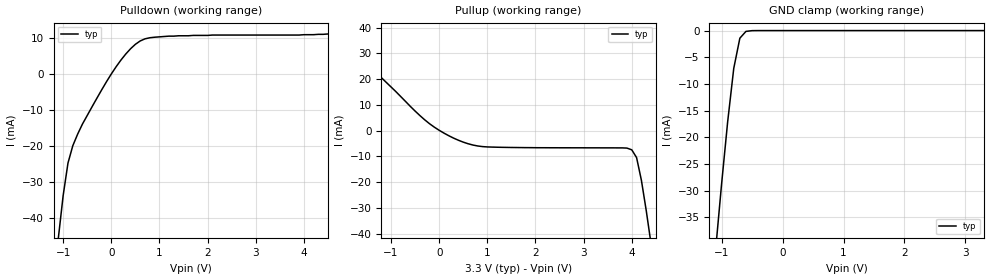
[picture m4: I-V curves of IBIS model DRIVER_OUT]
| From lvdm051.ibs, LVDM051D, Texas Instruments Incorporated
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|   Driver Output  MODEL
[Model]   DRIVER_OUT
Model_type   3-state
| Signals   1Y,1Z,2Y,2Z
Vmeas = 1.2V   |Reference voltage for timing measurements
Cref = 5pF   |Timing specification test load capacitance value
Rref = 50   |Note: 50 Ohm load; single ended configuration
Vref = 1.18V   |Timing specification test load voltage
| variable   typ   min   max
C_comp   1.0pF   NA   NA
|   typ   min   max
[Temperature Range]   25.0   NA   NA
[Voltage range]   3.3V   3.0V   3.6V
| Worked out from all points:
|   slope of the pulldown table from 0 to 0.495 V, typ, clamps not added: 60.6 ohm
|   slope of the pullup table from 0 to 0.495 V, typ, clamps not added: 109 ohm
|   GND clamp passes 1 mA (typ) near -0.67 V on its own axis
[Pulldown]
|   Voltage   I(typ)   I(min)   I(max)
-3.3V     -370mA     NA         NA
-1.1V     -45.6mA    NA         NA
-1V       -33.8mA    NA         NA
-900mV    -24.8mA    NA         NA
-800mV    -20mA      NA         NA
-700mV    -16.8mA    NA         NA
-300mV    -6.83mA    NA         NA
100mV     1.91mA     NA         NA
400mV     6.9mA      NA         NA
700mV     9.65mA     NA         NA
1.4V      10.5mA     NA         NA
6.6V      12.4mA     NA         NA
[Pullup]
|   Voltage   I(typ)   I(min)   I(max)
| Note that the[Pullup]voltage table is referenced to Vcc
| and is calculated using Vtable=Vcc - Vmeasured.
-3.3V     64.5mA     NA         NA
-2.2V     40.1mA     NA         NA
-400mV    5.79mA     NA         NA
0V        84.2uA     NA         NA
500mV     -4.51mA    NA         NA
1V        -6.37mA    NA         NA
4V        -7.49mA    NA         NA
4.1V      -10.5mA    NA         NA
4.2V      -19.3mA    NA         NA
4.3V      -31mA      NA         NA
4.4V      -43.9mA    NA         NA
6.6V      -370mA     NA         NA
[GND_clamp]
|   Voltage   I(typ)   I(min)   I(max)
| Outputs in High Impedance (off)
-3.3V     -347mA     NA         NA
-1.1V     -41.4mA    NA         NA
-1V       -28.8mA    NA         NA
-900mV    -17.1mA    NA         NA
-800mV    -7.08mA    NA         NA
-700mV    -1.43mA    NA         NA
-600mV    -153uA     NA         NA
-400mV    -866nA     NA         NA
3.3V      -59.7pA    NA         NA
[POWER_clamp]
|   Voltage   I(typ)   I(min)   I(max)
| Note that the [POWER_clamp] voltage table is referenced to Vcc
| and is calculated using Vtable = Vcc - Vmeasured.
| Outputs in Tri-state.
-3.3V     0A         NA         NA
0V        0A         NA         NA
[Ramp]
|   typ   min   max
dV/dt_r   0.314/1ps   NA   NA
dV/dt_f   0.443/1ps   NA   NA
R_load = 50ohm | Note: The measurement is on a differential configuration
